VERSION 5.8 ;
BUSBITCHARS "[]" ;
DIVIDERCHAR "/" ;

# Minimal layer definition for standalone validation
LAYER met1
  TYPE ROUTING ;
  DIRECTION HORIZONTAL ;
  PITCH 0.46 ;
  WIDTH 0.14 ;
END met1

# Site definition for 1T1R placement
SITE fecim_1t1r_site
  CLASS CORE ;
  SIZE 0.920 BY 3.400 ;
  SYMMETRY X Y ;
END fecim_1t1r_site

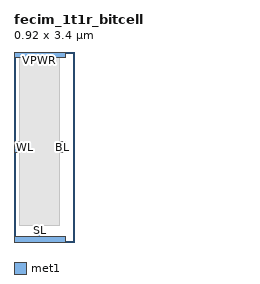
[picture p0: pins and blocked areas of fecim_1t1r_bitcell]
MACRO fecim_1t1r_bitcell
  CLASS CORE ;
  ORIGIN 0 0 ;
  SIZE 0.920 BY 3.400 ;
  SYMMETRY X Y ;
  SITE fecim_1t1r_site ;

  PIN WL
    DIRECTION INPUT ;
    USE SIGNAL ;
    PORT
      LAYER met1 ;
      RECT 0.000 1.600 0.100 1.800 ;
    END
  END WL

  PIN BL
    DIRECTION OUTPUT ;
    USE SIGNAL ;
    PORT
      LAYER met1 ;
      RECT 0.820 1.600 0.920 1.800 ;
    END
  END BL

  PIN SL
    DIRECTION INPUT ;
    USE SIGNAL ;
    PORT
      LAYER met1 ;
      RECT 0.410 0.100 0.510 0.300 ;
    END
  END SL

  PIN VPWR
    DIRECTION INOUT ;
    USE POWER ;
    PORT
      LAYER met1 ;
      RECT 0.000 3.300 0.920 3.400 ;
    END
  END VPWR

  PIN VGND
    DIRECTION INOUT ;
    USE GROUND ;
    PORT
      LAYER met1 ;
      RECT 0.000 0.000 0.920 0.100 ;
    END
  END VGND

  OBS
    LAYER met1 ;
    RECT 0.100 0.300 0.820 3.300 ;
  END

END fecim_1t1r_bitcell

END LIBRARY
